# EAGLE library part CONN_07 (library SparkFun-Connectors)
Multi connection point. Often used as Generic Header-pin footprint for 0.1 inch spaced/style header connections On any of the 0.1 inch spaced packages, you can populate with these: Break Away Headers - Straight (PRT-00116) Break Away Male Headers - Right Angle (PRT-00553) Female Headers (PRT-00115) Break Away Headers - Machine Pin (PRT-00117) Break Away Female Headers - Swiss Machine Pin (PRT-00743) For SCREWTERMINALS and SPRING TERMINALS visit here: Screw Terimnals on SparkFun.com (5mm/3.5mm/2.54mm spacing) This device is also useful as a general connection point to wire up your design to another part of your project. Our various solder wires solder well into these plated through hole pads. Hook-Up Wire - Assortment (Stranded, 22 AWG) (PRT-11375) Hook-Up Wire - Assortment (Solid Core, 22 AWG) (PRT-11367) View the entire wire category on our website here Special notes: Molex polarized connector foot print use with SKU : PRT-08231 with associated crimp pins and housings. 1MM SMD Version SKU: PRT-10208 NOTES ON THE VARIANTS LOCK and LOCK_LONGPADS... This footprint was designed to help hold the alignment of a through-hole component (i.e. 6-pin header) while soldering it into place. You may notice that each hole has been shifted either up or down by 0.005 of an inch from it's more standard position (which is a perfectly straight line). This slight alteration caused the pins (the squares in the middle) to touch the edges of the holes. Because they are alternating, it causes a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

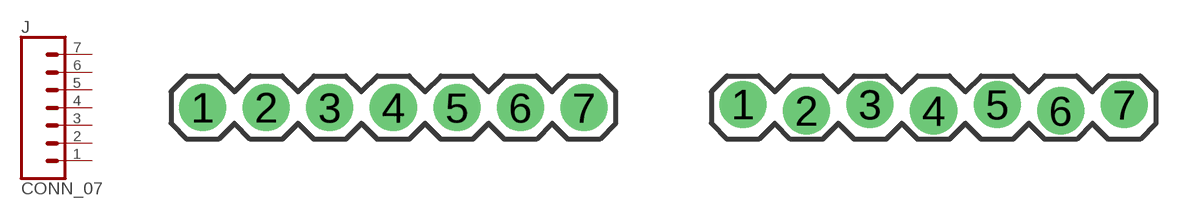
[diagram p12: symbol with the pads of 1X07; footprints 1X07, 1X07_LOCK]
Designator prefix J

## CONN_07  [1X07]
1  1  pas
2  2  pas
3  3  pas
4  4  pas
5  5  pas
6  6  pas
7  7  pas

## CONN_07LOCK  [1X07_LOCK]
Pads as for 1X07

## CONN_07LOCK_LONGPADS  [1X07_LOCK_LONGPADS]
Pads as for 1X07

## CONN_07LONGPADS  [1X07_LONGPADS]
Pads as for 1X07

## CONN_07POGOPINS_HOLES_ONLY  [1X07_HOLES_ONLY]
Pads as for 1X07

## CONN_07NO_SILK  [1X07_NO_SILK]
Pads as for 1X07

## CONN_073.5MM-7 (PROD_ID: Combine 8288+14485)  [SCREWTERMINAL-3.5MM-7]
Pads as for 1X07

## CONN_07LOCK_NO_SILK  [1X07_LOCK_NO_SILK]
Pads as for 1X07

## Footprint 1X07 (pad centres in mm)
Plated Through Hole -7 Pin Specifications: Pin count:7 Pin pitch:0.1" Example device(s): CONN_07
drill 1.016 pad 1.88: 1 0,0; 2 2.54,0; 3 5.08,0; 4 7.62,0; 5 10.16,0; 6 12.7,0; 7 15.24,0

## Footprint 1X07_LOCK (pad centres in mm)
Plated Through Hole -7 Pin Locking Footprint Holes are offset 0.005" from center, locking pins in place during soldering. Specifications: Pin count:7 Pin pitch:0.1" Example device(s): CONN_07
drill 1.016 pad 1.88: 1 0,0.127; 2 2.54,-0.127; 3 5.08,0.127; 4 7.62,-0.127; 5 10.16,0.127; 6 12.7,-0.127; 7 15.24,0.127

## Footprint 1X07_LOCK_LONGPADS (pad centres in mm)
Plated Through Hole -7 Pin Locking Footprint w/ Long Pads Holes are offset 0.005" from center, locking pins in place during soldering. Specifications: Pin count:7 Pin pitch:0.1" Example device(s):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
drill 1.016 long: 1 0,0.127; 2 2.54,-0.127; 3 5.08,0.127; 4 7.62,-0.127; 5 10.16,0.127; 6 12.7,-0.127; 7 15.24,0.127

## Footprint 1X07_LONGPADS (pad centres in mm)
Plated Through Hole -7 Pin Long Pads Specifications: Pin count:7 Pin pitch:0.1" Example device(s): CONN_07
drill 1.016 pad 1.88 long: 1 0,0; 2 2.54,0; 3 5.08,0; 4 7.62,0; 5 10.16,0; 6 12.7,0; 7 15.24,0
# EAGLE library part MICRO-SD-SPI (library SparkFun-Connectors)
microSD Socket for Transflash Push-push type µSD socket. tDoc lines correctly indicate media card edge positions when inserting (unlocked, locked, depressed). NOTE: CD1 and CD2 are connected internally, and the default detect state of the socket is detect pin to ground. SparkFun Products: WAV Trigger CAN-Bus Shield SparkFun Level Shifing microSD Breakout

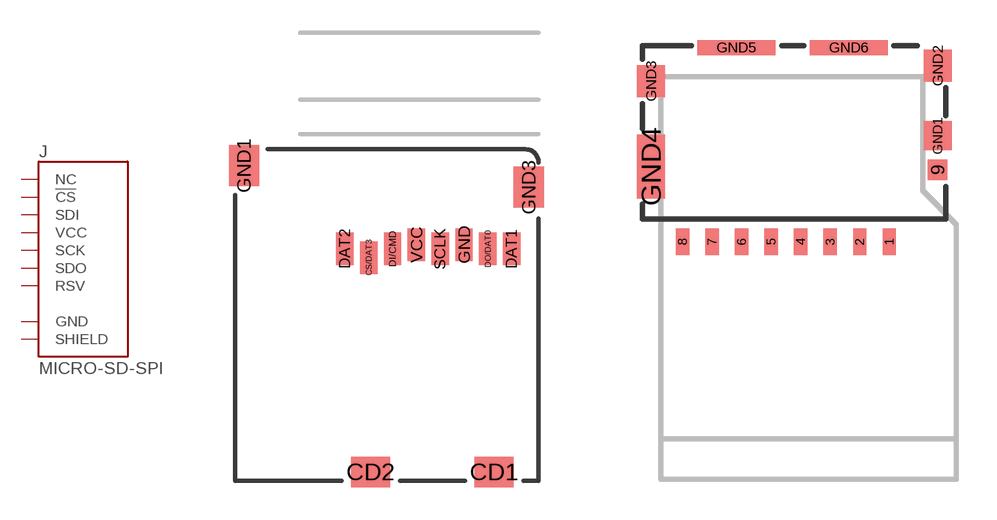
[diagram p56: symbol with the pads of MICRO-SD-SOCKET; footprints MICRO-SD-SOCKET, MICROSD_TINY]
Designator prefix J

## MICRO-SD-SPIPUSH-PUSH (PROD_ID: CONN-07820)  [MICRO-SD-SOCKET]
CD1  SHIELD
CS/DAT3  !CS!
DAT1  NC
DAT2  RSV
DI/CMD  SDI
DO/DAT0  SDO
GND  GND
SCLK  SCK
VCC  VCC

## MICRO-SD-SPITINY (PROD_ID: CONN-13500)  [MICROSD_TINY]
1  RSV
2  !CS!
3  SDI
4  VCC
5  SCK
6  GND
7  SDO
8  RSV
9  NC
GND1  SHIELD
GND2  SHIELD
GND3  SHIELD
GND4  SHIELD
GND5  SHIELD
GND6  SHIELD

## Footprint MICRO-SD-SOCKET (pad centres in mm)
microSD Socket SMD Puhs-Push type. tDocu shows location of uSD card in different positions. Specifications: Pin count:12 Datasheet referenced for footprint Example device(s): MICRO-SD_CARD_SOCKET
smd 1.8 x 1.4: CD1 -2.05,0.4; CD2 -7.75,0.4
smd 0.8 x 1.5: CS/DAT3 -7.84,10.3; DAT1 -1.24,10.7; DAT2 -8.94,10.7; DI/CMD -6.74,10.7; DO/DAT0 -2.34,10.7; GND -3.44,10.9; SCLK -4.54,10.7; VCC -5.64,10.9
smd 1.4 x 1.9: GND1 -13.6,14.55; GND3 -0.45,13.55

## Footprint MICROSD_TINY (pad centres in mm)
smd 0.5 x 1: 1 9.2,-0.85; 2 8.1,-0.85; 3 7,-0.85; 4 5.9,-0.85; 5 4.8,-0.85; 6 3.7,-0.85; 7 2.6,-0.85; 8 1.5,-0.85
smd 0.72 x 0.78: 9 11,1.83
smd 1.05 x 1.08: GND1 11,3.1
smd 1.05 x 1.2: GND2 11,5.71; GND3 0.325,5.14
smd 1.05 x 2.39: GND4 0.325,1.955
smd 2.91 x 0.55: GND5 3.505,6.385; GND6 7.695,6.385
